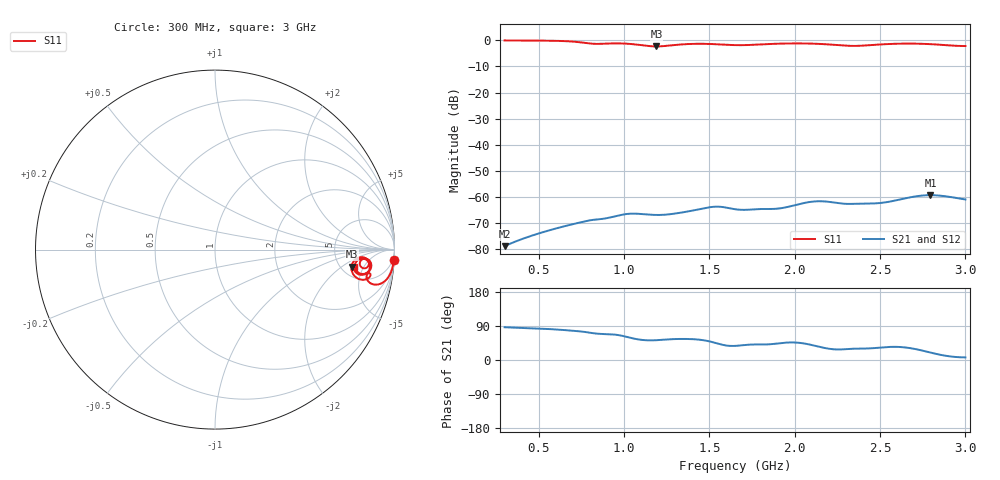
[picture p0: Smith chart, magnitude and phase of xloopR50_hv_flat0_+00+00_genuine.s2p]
! xloopR50_hv_flat0_+00+00_genuine, gap C 0.80 pF
! simulated by sim/fixtures_fdtd.py (S12 = S21, S22 not computed)
# HZ S RI R 50
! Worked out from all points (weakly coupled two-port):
!   541 points, 300 MHz to 3 GHz, reference 50 ohm
!   highest |S21| = -59.41 dB at 2.795 GHz (marker M1); lowest = -79.0 dB at 300 MHz (marker M2)
!   lowest |S11| = -2.3 dB at 1.19 GHz (marker M3), VSWR 7.57, Z = 312 - j143 ohm
!   |S11| at or under -10 dB: nowhere
!   |S22| runs from - to - dB; largest |S21 - S12| = 0
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3e8  0.9963 -0.0606  7e-06 0.000112  7e-06 0.000112  0 0
6e8  0.9703 -0.1465  4.01e-05 0.000242  4.01e-05 0.000242  0 0
7.5e8  0.8927 -0.1951  8.36e-05 0.000314  8.36e-05 0.000314  0 0
8.15e8  0.847 -0.1657  0.000117 0.000339  0.000117 0.000339  0 0
8.85e8  0.8558 -0.132  0.000139 0.000354  0.000139 0.000354  0 0
1.02e9  0.8481 -0.1632  0.00023 0.000407  0.00023 0.000407  0 0
1.105e9  0.7925 -0.1593  0.00028 0.000371  0.00028 0.000371  0 0
1.19e9  0.7607 -0.0944  0.000273 0.000353  0.000273 0.000353  0 0
1.2e9  0.7625 -0.0856  0.000271 0.000354  0.000271 0.000354  0 0
1.305e9  0.82 -0.0423  0.000272 0.000393  0.000272 0.000393  0 0
1.41e9  0.8564 -0.0687  0.000316 0.000449  0.000316 0.000449  0 0
1.525e9  0.843 -0.1017  0.000442 0.000463  0.000442 0.000463  0 0
1.65e9  0.8077 -0.0859  0.000458 0.000348  0.000458 0.000348  0 0
1.775e9  0.8279 -0.0511  0.000435 0.000378  0.000435 0.000378  0 0
1.9e9  0.8625 -0.0633  0.000427 0.000408  0.000427 0.000408  0 0
2.1e9  0.8597 -0.1192  0.000618 0.00051  0.000618 0.00051  0 0
2.225e9  0.8142 -0.1346  0.000684 0.000369  0.000684 0.000369  0 0
2.335e9  0.7792 -0.0935  0.000633 0.00036  0.000633 0.00036  0 0
2.44e9  0.809 -0.0519  0.000636 0.000377  0.000636 0.000377  0 0
2.55e9  0.8507 -0.0629  0.000658 0.00045  0.000658 0.00045  0 0
2.795e9  0.8372 -0.1362  0.00101 0.000361  0.00101 0.000361  0 0
3e9  0.774 -0.0947  0.000878 0.000106  0.000878 0.000106  0 0
